VERSION 5.7 ;
  NOWIREEXTENSIONATPIN ON ;
  DIVIDERCHAR "/" ;
  BUSBITCHARS "[]" ;
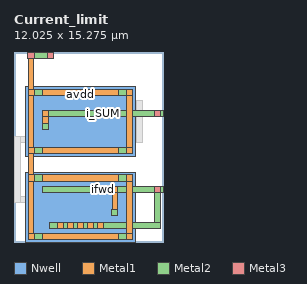
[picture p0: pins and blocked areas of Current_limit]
MACRO Current_limit
  CLASS BLOCK ;
  FOREIGN Current_limit ;
  ORIGIN 5.330 9.700 ;
  SIZE 12.025 BY 15.275 ;
  PIN avdd
    ANTENNADIFFAREA 18.172800 ;
    PORT
      LAYER Nwell ;
        RECT -4.430 -2.800 4.430 2.800 ;
        RECT -4.430 -9.700 4.430 -4.100 ;
      LAYER Metal1 ;
        RECT -4.220 5.075 -3.720 5.575 ;
        RECT -4.200 2.590 -3.740 5.075 ;
        RECT -4.200 2.090 -3.700 2.590 ;
        RECT -3.050 2.090 3.050 2.590 ;
        RECT 3.700 2.090 4.200 2.590 ;
        RECT -4.200 -2.090 -3.740 2.090 ;
        RECT 3.740 -2.090 4.200 2.090 ;
        RECT -4.200 -2.590 -3.700 -2.090 ;
        RECT -3.050 -2.590 3.050 -2.090 ;
        RECT 3.700 -2.590 4.200 -2.090 ;
        RECT -4.200 -4.310 -3.740 -2.590 ;
        RECT -4.200 -4.810 -3.700 -4.310 ;
        RECT -3.050 -4.810 3.050 -4.310 ;
        RECT 3.700 -4.810 4.200 -4.310 ;
        RECT -4.200 -8.990 -3.740 -4.810 ;
        RECT 3.740 -8.990 4.200 -4.810 ;
        RECT -4.200 -9.490 -3.700 -8.990 ;
        RECT -3.050 -9.490 3.050 -8.990 ;
        RECT 3.700 -9.490 4.200 -8.990 ;
      LAYER Metal2 ;
        RECT -4.220 5.075 -2.170 5.575 ;
        RECT -4.200 2.090 4.200 2.590 ;
        RECT -4.200 -2.590 4.200 -2.090 ;
        RECT -4.200 -4.810 4.200 -4.310 ;
        RECT -4.200 -9.490 4.200 -8.990 ;
      LAYER Metal3 ;
        RECT -4.220 5.075 -3.720 5.575 ;
        RECT -2.670 5.075 -2.170 5.575 ;
    END
  END avdd
  PIN i_SUM
    ANTENNADIFFAREA 0.300000 ;
    PORT
      LAYER Metal1 ;
        RECT -3.030 0.395 -2.530 0.895 ;
        RECT -3.010 -0.155 -2.550 0.395 ;
        RECT -3.030 -0.655 -2.530 -0.155 ;
      LAYER Metal2 ;
        RECT -3.030 0.395 6.695 0.895 ;
        RECT -3.030 -0.655 -2.530 -0.155 ;
      LAYER Metal3 ;
        RECT 5.945 0.395 6.445 0.895 ;
    END
  END i_SUM
  PIN ifwd
    ANTENNAGATEAREA 2.500000 ;
    ANTENNADIFFAREA 0.300000 ;
    PORT
      LAYER Metal1 ;
        RECT 2.530 -5.705 3.030 -5.205 ;
        RECT 2.550 -7.055 3.010 -5.705 ;
        RECT 2.530 -7.555 3.030 -7.055 ;
        RECT -1.850 -8.595 -1.350 -8.095 ;
        RECT -1.050 -8.595 -0.550 -8.095 ;
        RECT -0.250 -8.595 0.250 -8.095 ;
        RECT 0.550 -8.595 1.050 -8.095 ;
        RECT 1.350 -8.595 1.850 -8.095 ;
      LAYER Metal2 ;
        RECT -3.030 -5.705 6.695 -5.205 ;
        RECT 2.530 -7.555 3.030 -7.055 ;
        RECT 5.945 -8.095 6.445 -5.705 ;
        RECT -2.500 -8.595 6.445 -8.095 ;
      LAYER Metal3 ;
        RECT 5.945 -5.705 6.445 -5.205 ;
    END
  END ifwd
  OBS
      LAYER Metal1 ;
        RECT 2.530 1.195 3.030 1.695 ;
        RECT 2.550 -0.155 3.010 1.195 ;
        RECT 2.530 -0.655 3.030 -0.155 ;
        RECT -1.850 -1.695 -1.350 -1.195 ;
        RECT -1.050 -1.695 -0.550 -1.195 ;
        RECT -0.250 -1.695 0.250 -1.195 ;
        RECT 0.550 -1.695 1.050 -1.195 ;
        RECT 1.350 -1.695 1.850 -1.195 ;
        RECT -3.030 -6.505 -2.530 -6.005 ;
        RECT -3.010 -7.055 -2.550 -6.505 ;
        RECT -3.030 -7.555 -2.530 -7.055 ;
      LAYER Metal2 ;
        RECT -3.030 1.195 5.030 1.695 ;
        RECT 2.530 -0.655 3.030 -0.155 ;
        RECT -5.330 -1.695 5.030 -1.195 ;
        RECT -5.330 -6.505 3.030 -6.005 ;
        RECT -3.030 -7.555 -2.530 -7.055 ;
      LAYER Metal3 ;
        RECT -5.330 -6.505 -4.830 -1.195 ;
        RECT 4.530 -1.695 5.030 1.695 ;
  END
END Current_limit
END LIBRARY

